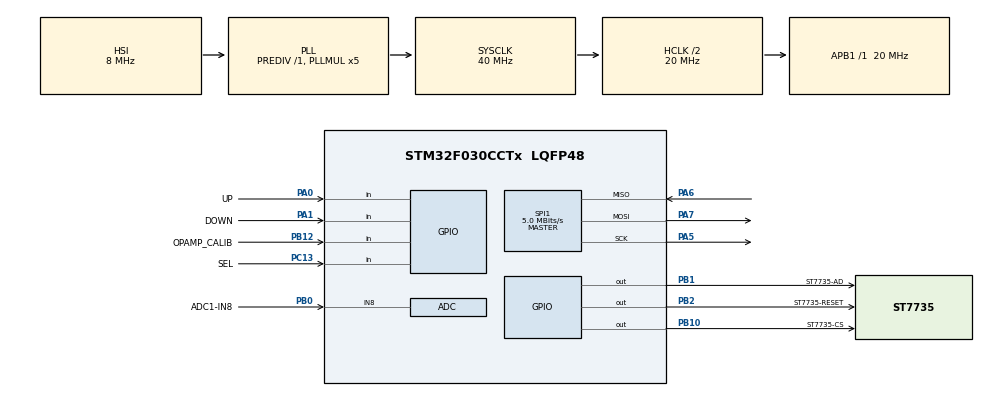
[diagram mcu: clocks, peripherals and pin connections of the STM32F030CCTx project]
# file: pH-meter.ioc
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Mcu.Family=STM32F0
Mcu.Name=STM32F030CCTx
Mcu.Package=LQFP48
PA0.GPIO_Label=UP
PA0.Signal=GPIO_Input
PA1.GPIO_Label=DOWN
PA1.GPIO_PuPd=GPIO_PULLUP
PA1.Signal=GPIO_Input
PA13.Mode=Serial_Wire
PA13.Signal=SYS_SWDIO
PA14.Mode=Serial_Wire
PA14.Signal=SYS_SWCLK
PA5.Mode=Full_Duplex_Master
PA5.Signal=SPI1_SCK
PA6.Mode=Full_Duplex_Master
PA6.Signal=SPI1_MISO
PA7.Mode=Full_Duplex_Master
PA7.Signal=SPI1_MOSI
PB0.GPIO_Label=ADC1-IN8
PB0.Signal=SharedAnalog_PB0
PB1.GPIO_Label=ST7735-AD
PB1.Signal=GPIO_Output
PB10.GPIO_Label=ST7735-CS
PB10.Signal=GPIO_Output
PB12.GPIO_Label=OPAMP_CALIB
PB12.GPIO_PuPd=GPIO_PULLUP
PB12.Signal=GPIO_Input
PB2.GPIO_Label=ST7735-RESET
PB2.Signal=GPIO_Output
PC13.GPIO_Label=SEL
PC13.GPIO_PuPd=GPIO_PULLUP
PC13.Signal=GPIO_Input
PC14OSC32_IN.GPIO_Label=RIGHT
PC14OSC32_IN.GPIO_PuPd=GPIO_PULLUP
PC14OSC32_IN.Signal=GPIO_Input
PC15OSC32_OUT.GPIO_Label=LEFT
PC15OSC32_OUT.GPIO_PuPd=GPIO_PULLUP
PC15OSC32_OUT.Signal=GPIO_Input
PF0-OSC_IN.Signal=RCC_OSC_IN
PF1-OSC_OUT.Signal=RCC_OSC_OUT
ProjectManager.HeapSize=0x200
ProjectManager.StackSize=0x400
ProjectManager.TargetToolchain=STM32CubeIDE
RCC.AHBCLKDivider=RCC_SYSCLK_DIV2
RCC.AHBFreq_Value=20000000
RCC.APB1Freq_Value=20000000
RCC.APB1TimFreq_Value=20000000
RCC.HCLKFreq_Value=20000000
RCC.PLLMUL=RCC_PLL_MUL5
RCC.SYSCLKFreq_VALUE=40000000
RCC.SYSCLKSource=RCC_SYSCLKSOURCE_PLLCLK
SH.SharedAnalog_PB0.0=GPIO_Analog
SH.SharedAnalog_PB0.1=ADC_IN8,IN8
SPI1.BaudRatePrescaler=SPI_BAUDRATEPRESCALER_4
SPI1.CalculateBaudRate=5.0 MBits/s
SPI1.DataSize=SPI_DATASIZE_8BIT
SPI1.Direction=SPI_DIRECTION_2LINES
SPI1.Mode=SPI_MODE_MASTER
SPI1.VirtualType=VM_MASTER
board=custom

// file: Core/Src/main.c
/* USER CODE BEGIN Header */
/**
  ******************************************************************************
  * @file           : main.c
  * @brief          : Main program body
  ******************************************************************************
  * @attention
  *
  * Copyright (c) 2023 STMicroelectronics.
  * All rights reserved.
  *
  * This software is licensed under terms that can be found in the LICENSE file
  * in the root directory of this software component.
  * If no LICENSE file comes with this software, it is provided AS-IS.
  *
  ******************************************************************************
  */
/* USER CODE END Header */
#include "main.h"

/* USER CODE BEGIN Includes */
#include "ST7735.h"
#include "GFX_FUNCTIONS.h"
#include "v_eeprom.h"
#include "pH_meter.h"
/* USER CODE END Includes */

 ADC_HandleTypeDef hadc;

SPI_HandleTypeDef hspi1;

void SystemClock_Config(void);
static void MX_GPIO_Init(void);
static void MX_ADC_Init(void);
static void MX_SPI1_Init(void);

int main(void)
{

  /* MCU Configuration--------------------------------------------------------*/

  /* Reset of all peripherals, Initializes the Flash interface and the Systick. */
  HAL_Init();

  /* Configure the system clock */
  SystemClock_Config();

  /* Initialize all configured peripherals */
  MX_GPIO_Init();
  MX_ADC_Init();
  MX_SPI1_Init();
  /* USER CODE BEGIN 2 */

  HAL_ADC_Start(&hadc);

  ST7735_Init(0);
  fillScreen(BLACK);
  HAL_Delay(500);

  /* USER CODE END 2 */

  /* Infinite loop */
  while (1)
  {

	  pHMeter_process();

  }
}

void SystemClock_Config(void)
{
  RCC_OscInitTypeDef RCC_OscInitStruct = {0};
  RCC_ClkInitTypeDef RCC_ClkInitStruct = {0};

  /** Initializes the RCC Oscillators according to the specified parameters
  * in the RCC_OscInitTypeDef structure.
  */
  RCC_OscInitStruct.OscillatorType = RCC_OSCILLATORTYPE_HSI|RCC_OSCILLATORTYPE_HSI14;
  RCC_OscInitStruct.HSIState = RCC_HSI_ON;
  RCC_OscInitStruct.HSI14State = RCC_HSI14_ON;
  RCC_OscInitStruct.HSICalibrationValue = RCC_HSICALIBRATION_DEFAULT;
  RCC_OscInitStruct.HSI14CalibrationValue = 16;
  RCC_OscInitStruct.PLL.PLLState = RCC_PLL_ON;
  RCC_OscInitStruct.PLL.PLLSource = RCC_PLLSOURCE_HSI;
  RCC_OscInitStruct.PLL.PLLMUL = RCC_PLL_MUL5;
  RCC_OscInitStruct.PLL.PREDIV = RCC_PREDIV_DIV1;
  if (HAL_RCC_OscConfig(&RCC_OscInitStruct) != HAL_OK)
  {
    Error_Handler();
  }

  /** Initializes the CPU, AHB and APB buses clocks
  */
  RCC_ClkInitStruct.ClockType = RCC_CLOCKTYPE_HCLK|RCC_CLOCKTYPE_SYSCLK
                              |RCC_CLOCKTYPE_PCLK1;
  RCC_ClkInitStruct.SYSCLKSource = RCC_SYSCLKSOURCE_PLLCLK;
  RCC_ClkInitStruct.AHBCLKDivider = RCC_SYSCLK_DIV2;
  RCC_ClkInitStruct.APB1CLKDivider = RCC_HCLK_DIV1;

  if (HAL_RCC_ClockConfig(&RCC_ClkInitStruct, FLASH_LATENCY_1) != HAL_OK)
  {
    Error_Handler();
  }
}

static void MX_ADC_Init(void)
{

  ADC_ChannelConfTypeDef sConfig = {0};

  /** Configure the global features of the ADC (Clock, Resolution, Data Alignment and number of conversion)
  */
  hadc.Instance = ADC1;
  hadc.Init.ClockPrescaler = ADC_CLOCK_ASYNC_DIV1;
  hadc.Init.Resolution = ADC_RESOLUTION_12B;
  hadc.Init.DataAlign = ADC_DATAALIGN_RIGHT;
  hadc.Init.ScanConvMode = ADC_SCAN_DIRECTION_FORWARD;
  hadc.Init.EOCSelection = ADC_EOC_SINGLE_CONV;
  hadc.Init.LowPowerAutoWait = DISABLE;
  hadc.Init.LowPowerAutoPowerOff = DISABLE;
  hadc.Init.ContinuousConvMode = DISABLE;
  hadc.Init.DiscontinuousConvMode = DISABLE;
  hadc.Init.ExternalTrigConv = ADC_SOFTWARE_START;
  hadc.Init.ExternalTrigConvEdge = ADC_EXTERNALTRIGCONVEDGE_NONE;
  hadc.Init.DMAContinuousRequests = DISABLE;
  hadc.Init.Overrun = ADC_OVR_DATA_PRESERVED;
  if (HAL_ADC_Init(&hadc) != HAL_OK)
  {
    Error_Handler();
  }

  /** Configure for the selected ADC regular channel to be converted.
  */
  sConfig.Channel = ADC_CHANNEL_8;
  sConfig.Rank = ADC_RANK_CHANNEL_NUMBER;
  sConfig.SamplingTime = ADC_SAMPLETIME_1CYCLE_5;
  if (HAL_ADC_ConfigChannel(&hadc, &sConfig) != HAL_OK)
  {
    Error_Handler();
  }

}

static void MX_SPI1_Init(void)
{

  /* SPI1 parameter configuration*/
  hspi1.Instance = SPI1;
  hspi1.Init.Mode = SPI_MODE_MASTER;
  hspi1.Init.Direction = SPI_DIRECTION_2LINES;
  hspi1.Init.DataSize = SPI_DATASIZE_8BIT;
  hspi1.Init.CLKPolarity = SPI_POLARITY_LOW;
  hspi1.Init.CLKPhase = SPI_PHASE_1EDGE;
  hspi1.Init.NSS = SPI_NSS_SOFT;
  hspi1.Init.BaudRatePrescaler = SPI_BAUDRATEPRESCALER_4;
  hspi1.Init.FirstBit = SPI_FIRSTBIT_MSB;
  hspi1.Init.TIMode = SPI_TIMODE_DISABLE;
  hspi1.Init.CRCCalculation = SPI_CRCCALCULATION_DISABLE;
  hspi1.Init.CRCPolynomial = 7;
  hspi1.Init.CRCLength = SPI_CRC_LENGTH_DATASIZE;
  hspi1.Init.NSSPMode = SPI_NSS_PULSE_ENABLE;
  if (HAL_SPI_Init(&hspi1) != HAL_OK)
  {
    Error_Handler();
  }

}

static void MX_GPIO_Init(void)
{
  GPIO_InitTypeDef GPIO_InitStruct = {0};

  /* GPIO Ports Clock Enable */
  __HAL_RCC_GPIOC_CLK_ENABLE();
  __HAL_RCC_GPIOF_CLK_ENABLE();
  __HAL_RCC_GPIOA_CLK_ENABLE();
  __HAL_RCC_GPIOB_CLK_ENABLE();

  /*Configure GPIO pin Output Level */
  HAL_GPIO_WritePin(GPIOB, ST7735_AD_Pin|ST7735_RESET_Pin|ST7735_CS_Pin, GPIO_PIN_RESET);

  /*Configure GPIO pins : SEL_Pin RIGHT_Pin LEFT_Pin */
  GPIO_InitStruct.Pin = SEL_Pin|RIGHT_Pin|LEFT_Pin;
  GPIO_InitStruct.Mode = GPIO_MODE_INPUT;
  GPIO_InitStruct.Pull = GPIO_PULLUP;
  HAL_GPIO_Init(GPIOC, &GPIO_InitStruct);

  /*Configure GPIO pin : UP_Pin */
  GPIO_InitStruct.Pin = UP_Pin;
  GPIO_InitStruct.Mode = GPIO_MODE_INPUT;
  GPIO_InitStruct.Pull = GPIO_NOPULL;
  HAL_GPIO_Init(UP_GPIO_Port, &GPIO_InitStruct);

  /*Configure GPIO pin : DOWN_Pin */
  GPIO_InitStruct.Pin = DOWN_Pin;
  GPIO_InitStruct.Mode = GPIO_MODE_INPUT;
  GPIO_InitStruct.Pull = GPIO_PULLUP;
  HAL_GPIO_Init(DOWN_GPIO_Port, &GPIO_InitStruct);

  /*Configure GPIO pins : ST7735_AD_Pin ST7735_RESET_Pin ST7735_CS_Pin */
  GPIO_InitStruct.Pin = ST7735_AD_Pin|ST7735_RESET_Pin|ST7735_CS_Pin;
  GPIO_InitStruct.Mode = GPIO_MODE_OUTPUT_PP;
  GPIO_InitStruct.Pull = GPIO_NOPULL;
  GPIO_InitStruct.Speed = GPIO_SPEED_FREQ_LOW;
  HAL_GPIO_Init(GPIOB, &GPIO_InitStruct);

  /*Configure GPIO pin : OPAMP_CALIB_Pin */
  GPIO_InitStruct.Pin = OPAMP_CALIB_Pin;
  GPIO_InitStruct.Mode = GPIO_MODE_INPUT;
  GPIO_InitStruct.Pull = GPIO_PULLUP;
  HAL_GPIO_Init(OPAMP_CALIB_GPIO_Port, &GPIO_InitStruct);

}

void Error_Handler(void)
{
  __disable_irq();
  while (1)
  {
  }
}
